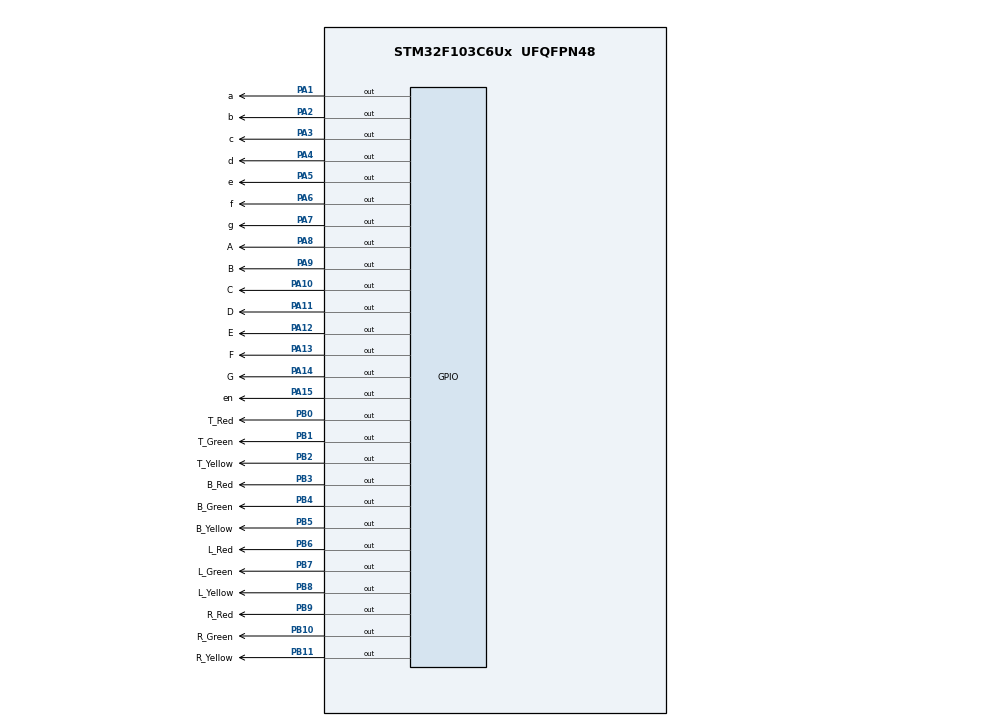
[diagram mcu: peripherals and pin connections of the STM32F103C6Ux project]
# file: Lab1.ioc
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Mcu.Family=STM32F1
Mcu.Name=STM32F103C6Ux
Mcu.Package=UFQFPN48
NVIC.PriorityGroup=NVIC_PRIORITYGROUP_4
PA1.GPIO_Label=a
PA1.Signal=GPIO_Output
PA10.GPIO_Label=C
PA10.Signal=GPIO_Output
PA11.GPIO_Label=D
PA11.Signal=GPIO_Output
PA12.GPIO_Label=E
PA12.Signal=GPIO_Output
PA13.GPIO_Label=F
PA13.Signal=GPIO_Output
PA14.GPIO_Label=G
PA14.Signal=GPIO_Output
PA15.GPIO_Label=en
PA15.Signal=GPIO_Output
PA2.GPIO_Label=b
PA2.Signal=GPIO_Output
PA3.GPIO_Label=c
PA3.Signal=GPIO_Output
PA4.GPIO_Label=d
PA4.Signal=GPIO_Output
PA5.GPIO_Label=e
PA5.Signal=GPIO_Output
PA6.GPIO_Label=f
PA6.Signal=GPIO_Output
PA7.GPIO_Label=g
PA7.Signal=GPIO_Output
PA8.GPIO_Label=A
PA8.Signal=GPIO_Output
PA9.GPIO_Label=B
PA9.Signal=GPIO_Output
PB0.GPIO_Label=T_Red
PB0.Signal=GPIO_Output
PB1.GPIO_Label=T_Green
PB1.Signal=GPIO_Output
PB10.GPIO_Label=R_Green
PB10.Signal=GPIO_Output
PB11.GPIO_Label=R_Yellow
PB11.Signal=GPIO_Output
PB2.GPIO_Label=T_Yellow
PB2.Signal=GPIO_Output
PB3.GPIO_Label=B_Red
PB3.Signal=GPIO_Output
PB4.GPIO_Label=B_Green
PB4.Signal=GPIO_Output
PB5.GPIO_Label=B_Yellow
PB5.Signal=GPIO_Output
PB6.GPIO_Label=L_Red
PB6.Signal=GPIO_Output
PB7.GPIO_Label=L_Green
PB7.Signal=GPIO_Output
PB8.GPIO_Label=L_Yellow
PB8.Signal=GPIO_Output
PB9.GPIO_Label=R_Red
PB9.Signal=GPIO_Output
ProjectManager.HeapSize=0x200
ProjectManager.StackSize=0x400
ProjectManager.TargetToolchain=STM32CubeIDE
RCC.APB1Freq_Value=8000000
RCC.APB2Freq_Value=8000000
VP_SYS_VS_ND.Mode=No_Debug
board=custom

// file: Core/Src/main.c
/* USER CODE BEGIN Header */
/**
  ******************************************************************************
  * @file           : main.c
  * @brief          : Main program body
  ******************************************************************************
  * @attention
  *
  * <h2><center>&copy; Copyright (c) 2024 STMicroelectronics.
  * All rights reserved.</center></h2>
  *
  * This software component is licensed by ST under BSD 3-Clause license,
  * the "License"; You may not use this file except in compliance with the
  * License. You may obtain a copy of the License at:
  *                        opensource.org/licenses/BSD-3-Clause
  *
  ******************************************************************************
  */
/* USER CODE END Header */
#include "main.h"

/* USER CODE BEGIN Includes */
#include <stdio.h>
/* USER CODE END Includes */

void SystemClock_Config(void);
static void MX_GPIO_Init(void);

/* USER CODE BEGIN 0 */
const uint16_t pin[12] = {
    GPIO_PIN_2,  // PB2
    GPIO_PIN_0,  // PB0
    GPIO_PIN_10,  // PB10
    GPIO_PIN_11,  // PB11
    GPIO_PIN_9,  // PB9
    GPIO_PIN_4,  // PB4
    GPIO_PIN_5,  // PB5
    GPIO_PIN_3,  // PB3
    GPIO_PIN_7,  // PB7
    GPIO_PIN_8,  // PB8
    GPIO_PIN_6,  // PB6
    GPIO_PIN_1,  // PB1
};
void clearNumberOnClock(int num){
	HAL_GPIO_WritePin(GPIOB, pin[num], GPIO_PIN_RESET);
}
void setNumberOnClock(int num){
	HAL_GPIO_WritePin(GPIOB, pin[num], GPIO_PIN_SET);
}
void clearAllClock(){
	HAL_GPIO_WritePin(GPIOB, H1_Pin|H11_Pin|H12_Pin|H2_Pin
	                          |H3_Pin|H7_Pin|H5_Pin|H6_Pin
	                          |H10_Pin|H8_Pin|H9_Pin|H4_Pin, GPIO_PIN_RESET);
}
void setMH(int *m, int *h){
	(*m)++;
	if (*m >= 60) {
		*m = 0;
		(*h)++;
		if (*h >= 12) *h -= 12;
	}
}
void displayTime(int s, int m, int h){
	setNumberOnClock(s/5);
	setNumberOnClock(m/5);
	if (h >= 12) h -= 12;
	setNumberOnClock(h);
}

/* USER CODE END 0 */

int main(void)
{

  /* MCU Configuration--------------------------------------------------------*/

  /* Reset of all peripherals, Initializes the Flash interface and the Systick. */
  HAL_Init();

  /* Configure the system clock */
  SystemClock_Config();

  /* Initialize all configured peripherals */
  MX_GPIO_Init();

  /* Infinite loop */
  /* USER CODE BEGIN WHILE */
  int h = 15, m = 3, s = 24;
  int *pm = &m, *ph = &h;
  clearAllClock();
  while (1)
  {
	    clearAllClock();
	    if (s >= 60) {
	        s = 0;
	        setMH(pm, ph);
	    }
	    displayTime(s, m, h);
	    s++;
	    HAL_Delay(1000);
    /* USER CODE END WHILE */

  }
}

void SystemClock_Config(void)
{
  RCC_OscInitTypeDef RCC_OscInitStruct = {0};
  RCC_ClkInitTypeDef RCC_ClkInitStruct = {0};

  /** Initializes the RCC Oscillators according to the specified parameters
  * in the RCC_OscInitTypeDef structure.
  */
  RCC_OscInitStruct.OscillatorType = RCC_OSCILLATORTYPE_HSI;
  RCC_OscInitStruct.HSIState = RCC_HSI_ON;
  RCC_OscInitStruct.HSICalibrationValue = RCC_HSICALIBRATION_DEFAULT;
  RCC_OscInitStruct.PLL.PLLState = RCC_PLL_NONE;
  if (HAL_RCC_OscConfig(&RCC_OscInitStruct) != HAL_OK)
  {
    Error_Handler();
  }
  /** Initializes the CPU, AHB and APB buses clocks
  */
  RCC_ClkInitStruct.ClockType = RCC_CLOCKTYPE_HCLK|RCC_CLOCKTYPE_SYSCLK
                              |RCC_CLOCKTYPE_PCLK1|RCC_CLOCKTYPE_PCLK2;
  RCC_ClkInitStruct.SYSCLKSource = RCC_SYSCLKSOURCE_HSI;
  RCC_ClkInitStruct.AHBCLKDivider = RCC_SYSCLK_DIV1;
  RCC_ClkInitStruct.APB1CLKDivider = RCC_HCLK_DIV1;
  RCC_ClkInitStruct.APB2CLKDivider = RCC_HCLK_DIV1;

  if (HAL_RCC_ClockConfig(&RCC_ClkInitStruct, FLASH_LATENCY_0) != HAL_OK)
  {
    Error_Handler();
  }
}

static void MX_GPIO_Init(void)
{
  GPIO_InitTypeDef GPIO_InitStruct = {0};

  /* GPIO Ports Clock Enable */
  __HAL_RCC_GPIOB_CLK_ENABLE();

  /*Configure GPIO pin Output Level */
  HAL_GPIO_WritePin(GPIOB, H1_Pin|H11_Pin|H12_Pin|H2_Pin
                          |H3_Pin|H7_Pin|H5_Pin|H6_Pin
                          |H10_Pin|H8_Pin|H9_Pin|H4_Pin, GPIO_PIN_RESET);

  /*Configure GPIO pins : H1_Pin H11_Pin H12_Pin H2_Pin
                           H3_Pin H7_Pin H5_Pin H6_Pin
                           H10_Pin H8_Pin H9_Pin H4_Pin */
  GPIO_InitStruct.Pin = H1_Pin|H11_Pin|H12_Pin|H2_Pin
                          |H3_Pin|H7_Pin|H5_Pin|H6_Pin
                          |H10_Pin|H8_Pin|H9_Pin|H4_Pin;
  GPIO_InitStruct.Mode = GPIO_MODE_OUTPUT_PP;
  GPIO_InitStruct.Pull = GPIO_NOPULL;
  GPIO_InitStruct.Speed = GPIO_SPEED_FREQ_LOW;
  HAL_GPIO_Init(GPIOB, &GPIO_InitStruct);

}

void Error_Handler(void)
{
  __disable_irq();
  while (1)
  {
  }
}

/************************ (C) COPYRIGHT STMicroelectronics *****END OF FILE****/
